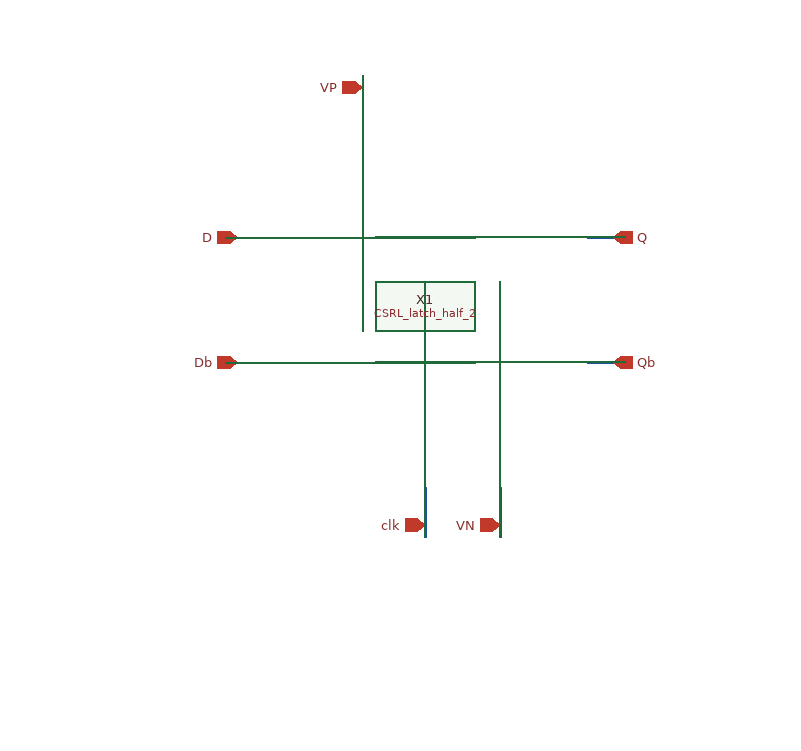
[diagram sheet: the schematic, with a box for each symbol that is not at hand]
v {xschem version=2.9.9 file_version=1.2 }
G {}
K {}
V {}
S {}
E {}
N 260 -440 260 -410 { lab=VP}
N 310 -110 310 -80 { lab=clk}
N 150 -310 180 -310 { lab=D}
N 150 -210 180 -210 { lab=Db}
N 310 -80 310 -70 { lab=clk}
N 370 -110 370 -70 { lab=VN}
N 440 -310 470 -310 { lab=Q}
N 440 -210 470 -210 { lab=Qb}
C {devices/ipin.sym} 160 -310 0 0 {name=p1 lab=D}
C {devices/ipin.sym} 160 -210 0 0 {name=p2 lab=Db}
C {devices/iopin.sym} 260 -430 3 0 {name=p3 lab=VP}
C {devices/iopin.sym} 370 -80 1 0 {name=p4 lab=VN}
C {devices/iopin.sym} 310 -80 1 0 {name=p5 lab=clk}
C {devices/opin.sym} 460 -310 0 0 {name=p6 lab=Q}
C {devices/opin.sym} 460 -210 0 0 {name=p7 lab=Qb}
C {/home/madvlsi/Documents/Mini_Project_2/half_CSRL_2/CSRL_latch_half_2.sym} 60 30 0 0 {name=X1}
